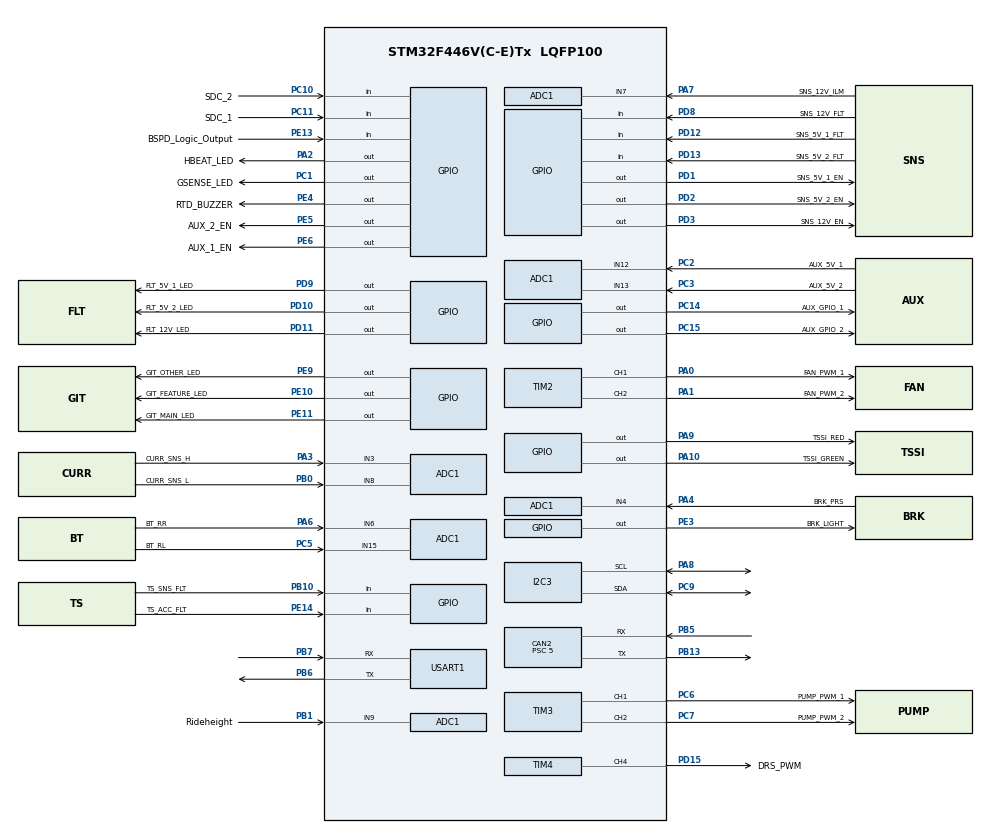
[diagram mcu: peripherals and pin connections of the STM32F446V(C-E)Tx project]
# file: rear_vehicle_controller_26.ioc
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ADC1.Channel-0\#ChannelRegularConversion=ADC_CHANNEL_3
ADC1.Channel-1\#ChannelRegularConversion=ADC_CHANNEL_4
ADC1.Channel-2\#ChannelRegularConversion=ADC_CHANNEL_6
ADC1.Channel-3\#ChannelRegularConversion=ADC_CHANNEL_7
ADC1.Channel-4\#ChannelRegularConversion=ADC_CHANNEL_8
ADC1.Channel-5\#ChannelRegularConversion=ADC_CHANNEL_9
ADC1.Channel-6\#ChannelRegularConversion=ADC_CHANNEL_12
ADC1.Channel-7\#ChannelRegularConversion=ADC_CHANNEL_13
ADC1.Channel-8\#ChannelRegularConversion=ADC_CHANNEL_15
ADC1.ClockPrescaler=ADC_CLOCK_SYNC_PCLK_DIV4
ADC1.ContinuousConvMode=ENABLE
ADC1.DMAContinuousRequests=ENABLE
ADC1.NbrOfConversion=9
ADC1.NbrOfConversionFlag=1
ADC1.Rank-0\#ChannelRegularConversion=1
ADC1.Rank-1\#ChannelRegularConversion=2
ADC1.Rank-2\#ChannelRegularConversion=3
ADC1.Rank-3\#ChannelRegularConversion=4
ADC1.Rank-4\#ChannelRegularConversion=5
ADC1.Rank-5\#ChannelRegularConversion=6
ADC1.Rank-6\#ChannelRegularConversion=7
ADC1.Rank-7\#ChannelRegularConversion=8
ADC1.Rank-8\#ChannelRegularConversion=9
ADC1.SamplingTime-0\#ChannelRegularConversion=ADC_SAMPLETIME_480CYCLES
ADC1.SamplingTime-1\#ChannelRegularConversion=ADC_SAMPLETIME_480CYCLES
ADC1.SamplingTime-2\#ChannelRegularConversion=ADC_SAMPLETIME_480CYCLES
ADC1.SamplingTime-3\#ChannelRegularConversion=ADC_SAMPLETIME_480CYCLES
ADC1.SamplingTime-4\#ChannelRegularConversion=ADC_SAMPLETIME_480CYCLES
ADC1.SamplingTime-5\#ChannelRegularConversion=ADC_SAMPLETIME_480CYCLES
ADC1.SamplingTime-6\#ChannelRegularConversion=ADC_SAMPLETIME_480CYCLES
ADC1.SamplingTime-7\#ChannelRegularConversion=ADC_SAMPLETIME_480CYCLES
ADC1.SamplingTime-8\#ChannelRegularConversion=ADC_SAMPLETIME_480CYCLES
ADC1.master=1
CAN2.ABOM=ENABLE
CAN2.AWUM=ENABLE
CAN2.BS1=CAN_BS1_6TQ
CAN2.CalculateBaudRate=1000000
CAN2.CalculateTimeBit=1000
CAN2.CalculateTimeQuantum=125.0
CAN2.Prescaler=5
Dma.ADC1.0.Direction=DMA_PERIPH_TO_MEMORY
Dma.ADC1.0.FIFOMode=DMA_FIFOMODE_DISABLE
Dma.ADC1.0.Instance=DMA2_Stream0
Dma.ADC1.0.MemDataAlignment=DMA_MDATAALIGN_HALFWORD
Dma.ADC1.0.MemInc=DMA_MINC_ENABLE
Dma.ADC1.0.Mode=DMA_CIRCULAR
Dma.ADC1.0.PeriphDataAlignment=DMA_PDATAALIGN_HALFWORD
Dma.ADC1.0.PeriphInc=DMA_PINC_DISABLE
Dma.ADC1.0.Priority=DMA_PRIORITY_LOW
Dma.Request0=ADC1
FREERTOS.Tasks01=main_task,0,1024,task_MainTask,Default,NULL,Dynamic,NULL,NULL;gcan_buffering,1,1024,gcanBufferHandling,Default,NULL,Dynamic,NULL,NULL
FREERTOS.configENABLE_FPU=1
Mcu.Family=STM32F4
Mcu.Name=STM32F446V(C-E)Tx
Mcu.Package=LQFP100
NVIC.CAN2_RX0_IRQn=true\:5\:0\:false\:false\:true\:true\:true\:true\:true
NVIC.CAN2_RX1_IRQn=true\:5\:0\:false\:false\:true\:true\:true\:true\:true
NVIC.CAN2_TX_IRQn=true\:5\:0\:false\:false\:true\:true\:true\:true\:true
NVIC.DMA2_Stream0_IRQn=true\:5\:0\:false\:false\:true\:true\:false\:true\:true
NVIC.PriorityGroup=NVIC_PRIORITYGROUP_4
NVIC.TIM1_UP_TIM10_IRQn=true\:5\:0\:false\:false\:true\:true\:true\:true\:true
NVIC.TIM6_DAC_IRQn=true\:15\:0\:false\:false\:true\:false\:false\:true\:true
NVIC.TimeBase=TIM6_DAC_IRQn
NVIC.TimeBaseIP=TIM6
PA0-WKUP.GPIO_Label=FAN_PWM_1
PA0-WKUP.Signal=S_TIM2_CH1_ETR
PA1.GPIO_Label=FAN_PWM_2
PA1.Signal=S_TIM2_CH2
PA10.GPIO_Label=TSSI_GREEN
PA10.Signal=GPIO_Output
PA13.Mode=Serial_Wire
PA13.Signal=SYS_JTMS-SWDIO
PA14.Mode=Serial_Wire
PA14.Signal=SYS_JTCK-SWCLK
PA2.GPIO_Label=HBEAT_LED
PA2.Signal=GPIO_Output
PA3.GPIO_Label=CURR_SNS_H
PA3.Signal=ADCx_IN3
PA4.GPIO_Label=BRK_PRS
PA4.Signal=ADCx_IN4
PA6.GPIO_Label=BT_RR
PA6.Signal=ADCx_IN6
PA7.GPIO_Label=SNS_12V_ILM
PA7.Signal=ADCx_IN7
PA8.Mode=I2C
PA8.Signal=I2C3_SCL
PA9.GPIO_Label=TSSI_RED
PA9.Signal=GPIO_Output
PB0.GPIO_Label=CURR_SNS_L
PB0.Signal=ADCx_IN8
PB1.GPIO_Label=Rideheight
PB1.Signal=ADCx_IN9
PB10.GPIO_Label=TS_SNS_FLT
PB10.Signal=GPIO_Input
PB13.Mode=CAN_Activate
PB13.Signal=CAN2_TX
PB3.Signal=SYS_JTDO-SWO
PB5.Mode=CAN_Activate
PB5.Signal=CAN2_RX
PB6.Mode=Asynchronous
PB6.Signal=USART1_TX
PB7.Mode=Asynchronous
PB7.Signal=USART1_RX
PC1.GPIO_Label=GSENSE_LED
PC1.Signal=GPIO_Output
PC10.GPIO_Label=SDC_2
PC10.Signal=GPIO_Input
PC11.GPIO_Label=SDC_1
PC11.Signal=GPIO_Input
PC14-OSC32_IN.GPIO_Label=AUX_GPIO_1
PC14-OSC32_IN.Signal=GPIO_Output
PC15-OSC32_OUT.GPIO_Label=AUX_GPIO_2
PC15-OSC32_OUT.Signal=GPIO_Output
PC2.GPIO_Label=AUX_5V_1
PC2.Signal=ADCx_IN12
PC3.GPIO_Label=AUX_5V_2
PC3.Signal=ADCx_IN13
PC5.GPIO_Label=BT_RL
PC5.Signal=ADCx_IN15
PC6.GPIO_Label=PUMP_PWM_1
PC6.Signal=S_TIM3_CH1
PC7.GPIO_Label=PUMP_PWM_2
PC7.Signal=S_TIM3_CH2
PC9.Mode=I2C
PC9.Signal=I2C3_SDA
PD1.GPIO_Label=SNS_5V_1_EN
PD1.Signal=GPIO_Output
PD10.GPIO_Label=FLT_5V_2_LED
PD10.Signal=GPIO_Output
PD11.GPIO_Label=FLT_12V_LED
PD11.Signal=GPIO_Output
PD12.GPIO_Label=SNS_5V_1_FLT
PD12.Signal=GPIO_Input
PD13.GPIO_Label=SNS_5V_2_FLT
PD13.Signal=GPIO_Input
PD15.GPIO_Label=DRS_PWM
PD15.Signal=S_TIM4_CH4
PD2.GPIO_Label=SNS_5V_2_EN
PD2.Signal=GPIO_Output
PD3.GPIO_Label=SNS_12V_EN
PD3.Signal=GPIO_Output
PD8.GPIO_Label=SNS_12V_FLT
PD8.Signal=GPIO_Input
PD9.GPIO_Label=FLT_5V_1_LED
PD9.Signal=GPIO_Output
PE10.GPIO_Label=GIT_FEATURE_LED
PE10.Signal=GPIO_Output
PE11.GPIO_Label=GIT_MAIN_LED
PE11.Signal=GPIO_Output
PE13.GPIO_Label=BSPD_Logic_Output
PE13.Signal=GPIO_Input
PE14.GPIO_Label=TS_ACC_FLT
PE14.Signal=GPIO_Input
PE3.GPIO_Label=BRK_LIGHT
PE3.Signal=GPIO_Output
PE4.GPIO_Label=RTD_BUZZER
PE4.Signal=GPIO_Output
PE5.GPIO_Label=AUX_2_EN
PE5.Signal=GPIO_Output
PE6.GPIO_Label=AUX_1_EN
PE6.Signal=GPIO_Output
PE9.GPIO_Label=GIT_OTHER_LED
PE9.Signal=GPIO_Output
PH0-OSC_IN.Mode=HSE-External-Clock-Source
PH0-OSC_IN.Signal=RCC_OSC_IN
PH1-OSC_OUT.Mode=HSE-External-Clock-Source
PH1-OSC_OUT.Signal=RCC_OSC_OUT
ProjectManager.HeapSize=0x200
ProjectManager.StackSize=0x400
ProjectManager.TargetToolchain=CMake
RCC.AHBFreq_Value=160000000
RCC.APB1CLKDivider=RCC_HCLK_DIV4
RCC.APB1Freq_Value=40000000
RCC.APB1TimFreq_Value=80000000
RCC.APB2CLKDivider=RCC_HCLK_DIV16
RCC.APB2Freq_Value=10000000
RCC.APB2TimFreq_Value=20000000
RCC.CortexFreq_Value=160000000
RCC.HCLKFreq_Value=160000000
RCC.HSE_VALUE=24000000
RCC.PLLM=12
RCC.PLLN=160
RCC.PLLSourceVirtual=RCC_PLLSOURCE_HSE
RCC.SYSCLKFreq_VALUE=160000000
RCC.SYSCLKSource=RCC_SYSCLKSOURCE_PLLCLK
RCC.USBFreq_Value=160000000
RCC.VCOOutputFreq_Value=320000000
SH.ADCx_IN12.0=ADC1_IN12,IN12
SH.ADCx_IN13.0=ADC1_IN13,IN13
SH.ADCx_IN15.0=ADC1_IN15,IN15
SH.ADCx_IN3.0=ADC1_IN3,IN3
SH.ADCx_IN4.0=ADC1_IN4,IN4
SH.ADCx_IN6.0=ADC1_IN6,IN6
SH.ADCx_IN7.0=ADC1_IN7,IN7
SH.ADCx_IN8.0=ADC1_IN8,IN8
SH.ADCx_IN9.0=ADC1_IN9,IN9
SH.S_TIM2_CH1_ETR.0=TIM2_CH1,PWM Generation1 CH1
SH.S_TIM2_CH2.0=TIM2_CH2,PWM Generation2 CH2
SH.S_TIM3_CH1.0=TIM3_CH1,PWM Generation1 CH1
SH.S_TIM3_CH2.0=TIM3_CH2,PWM Generation2 CH2
SH.S_TIM4_CH4.0=TIM4_CH4,PWM Generation4 CH4
TIM2.Channel-PWM\ Generation1\ CH1=TIM_CHANNEL_1
TIM2.Channel-PWM\ Generation2\ CH2=TIM_CHANNEL_2
TIM3.Channel-PWM\ Generation1\ CH1=TIM_CHANNEL_1
TIM3.Channel-PWM\ Generation2\ CH2=TIM_CHANNEL_2
TIM4.Channel-PWM\ Generation4\ CH4=TIM_CHANNEL_4
TIM4.Period=30100
TIM4.Prescaler=8-1
TIM4.Pulse-PWM\ Generation4\ CH4=30000
USART1.VirtualMode=VM_ASYNC
VP_FREERTOS_VS_CMSIS_V1.Mode=CMSIS_V1
VP_SYS_VS_tim6.Mode=TIM6
VP_TIM10_VS_ClockSourceINT.Mode=Enable_Timer
VP_TIM2_VS_ClockSourceINT.Mode=Internal
VP_TIM3_VS_ClockSourceINT.Mode=Internal
VP_TIM4_VS_ClockSourceINT.Mode=Internal
board=custom

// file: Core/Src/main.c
/* USER CODE BEGIN Header */
/**
  ******************************************************************************
  * @file           : main.c
  * @brief          : Main program body
  ******************************************************************************
  * @attention
  *
  * Copyright (c) 2025 STMicroelectronics.
  * All rights reserved.
  *
  * This software is licensed under terms that can be found in the LICENSE file
  * in the root directory of this software component.
  * If no LICENSE file comes with this software, it is provided AS-IS.
  *
  ******************************************************************************
  */
/* USER CODE END Header */
#include "main.h"
#include "cmsis_os.h"
#include "adc.h"
#include "can.h"
#include "dma.h"
#include "i2c.h"
#include "tim.h"
#include "usart.h"
#include "gpio.h"

/* USER CODE BEGIN Includes */
#include "rvc.h"
#include "GopherCAN.h"
#include "gopher_sense.h"
/* USER CODE END Includes */

void SystemClock_Config(void);
void MX_FREERTOS_Init(void);

int main(void)
{

  /* MCU Configuration--------------------------------------------------------*/

  /* Reset of all peripherals, Initializes the Flash interface and the Systick. */
  HAL_Init();

  /* Configure the system clock */
  SystemClock_Config();

  /* Initialize all configured peripherals */
  MX_GPIO_Init();
  MX_DMA_Init();
  MX_ADC1_Init();
  MX_CAN2_Init();
  MX_TIM10_Init();
  MX_I2C3_Init();
  MX_TIM2_Init();
  MX_TIM3_Init();
  MX_TIM4_Init();
  MX_USART1_UART_Init();
  /* USER CODE BEGIN 2 */
  init_rvc(&hcan2);
  gsense_init(&hcan2, &hadc1, NULL, NULL, &htim10, GSENSE_LED_GPIO_Port, GSENSE_LED_Pin);
  /* USER CODE END 2 */

  /* Call init function for freertos objects (in cmsis_os2.c) */
  MX_FREERTOS_Init();

  /* Start scheduler */
  osKernelStart();

  /* We should never get here as control is now taken by the scheduler */

  /* Infinite loop */
  while (1)
  {

  }
}

void SystemClock_Config(void)
{
  RCC_OscInitTypeDef RCC_OscInitStruct = {0};
  RCC_ClkInitTypeDef RCC_ClkInitStruct = {0};

  /** Configure the main internal regulator output voltage
  */
  __HAL_RCC_PWR_CLK_ENABLE();
  __HAL_PWR_VOLTAGESCALING_CONFIG(PWR_REGULATOR_VOLTAGE_SCALE1);

  /** Initializes the RCC Oscillators according to the specified parameters
  * in the RCC_OscInitTypeDef structure.
  */
  RCC_OscInitStruct.OscillatorType = RCC_OSCILLATORTYPE_HSE;
  RCC_OscInitStruct.HSEState = RCC_HSE_BYPASS;
  RCC_OscInitStruct.PLL.PLLState = RCC_PLL_ON;
  RCC_OscInitStruct.PLL.PLLSource = RCC_PLLSOURCE_HSE;
  RCC_OscInitStruct.PLL.PLLM = 12;
  RCC_OscInitStruct.PLL.PLLN = 160;
  RCC_OscInitStruct.PLL.PLLP = RCC_PLLP_DIV2;
  RCC_OscInitStruct.PLL.PLLQ = 2;
  RCC_OscInitStruct.PLL.PLLR = 2;
  if (HAL_RCC_OscConfig(&RCC_OscInitStruct) != HAL_OK)
  {
    Error_Handler();
  }

  /** Initializes the CPU, AHB and APB buses clocks
  */
  RCC_ClkInitStruct.ClockType = RCC_CLOCKTYPE_HCLK|RCC_CLOCKTYPE_SYSCLK
                              |RCC_CLOCKTYPE_PCLK1|RCC_CLOCKTYPE_PCLK2;
  RCC_ClkInitStruct.SYSCLKSource = RCC_SYSCLKSOURCE_PLLCLK;
  RCC_ClkInitStruct.AHBCLKDivider = RCC_SYSCLK_DIV1;
  RCC_ClkInitStruct.APB1CLKDivider = RCC_HCLK_DIV4;
  RCC_ClkInitStruct.APB2CLKDivider = RCC_HCLK_DIV2;

  if (HAL_RCC_ClockConfig(&RCC_ClkInitStruct, FLASH_LATENCY_5) != HAL_OK)
  {
    Error_Handler();
  }
}

static void MX_ADC1_Init(void)
{

  ADC_ChannelConfTypeDef sConfig = {0};

  /** Configure the global features of the ADC (Clock, Resolution, Data Alignment and number of conversion)
  */
  hadc1.Instance = ADC1;
  hadc1.Init.ClockPrescaler = ADC_CLOCK_SYNC_PCLK_DIV4;
  hadc1.Init.Resolution = ADC_RESOLUTION_12B;
  hadc1.Init.ScanConvMode = ENABLE;
  hadc1.Init.ContinuousConvMode = ENABLE;
  hadc1.Init.DiscontinuousConvMode = DISABLE;
  hadc1.Init.ExternalTrigConvEdge = ADC_EXTERNALTRIGCONVEDGE_NONE;
  hadc1.Init.ExternalTrigConv = ADC_SOFTWARE_START;
  hadc1.Init.DataAlign = ADC_DATAALIGN_RIGHT;
  hadc1.Init.NbrOfConversion = 9;
  hadc1.Init.DMAContinuousRequests = ENABLE;
  hadc1.Init.EOCSelection = ADC_EOC_SINGLE_CONV;
  if (HAL_ADC_Init(&hadc1) != HAL_OK)
  {
    Error_Handler();
  }

  /** Configure for the selected ADC regular channel its corresponding rank in the sequencer and its sample time.
  */
  sConfig.Channel = ADC_CHANNEL_3;
  sConfig.Rank = 1;
  sConfig.SamplingTime = ADC_SAMPLETIME_480CYCLES;
  if (HAL_ADC_ConfigChannel(&hadc1, &sConfig) != HAL_OK)
  {
    Error_Handler();
  }

  /** Configure for the selected ADC regular channel its corresponding rank in the sequencer and its sample time.
  */
  sConfig.Channel = ADC_CHANNEL_4;
  sConfig.Rank = 2;
  if (HAL_ADC_ConfigChannel(&hadc1, &sConfig) != HAL_OK)
  {
    Error_Handler();
  }

  /** Configure for the selected ADC regular channel its corresponding rank in the sequencer and its sample time.
  */
  sConfig.Channel = ADC_CHANNEL_6;
  sConfig.Rank = 3;
  if (HAL_ADC_ConfigChannel(&hadc1, &sConfig) != HAL_OK)
  {
    Error_Handler();
  }

  /** Configure for the selected ADC regular channel its corresponding rank in the sequencer and its sample time.
  */
  sConfig.Channel = ADC_CHANNEL_7;
  sConfig.Rank = 4;
  if (HAL_ADC_ConfigChannel(&hadc1, &sConfig) != HAL_OK)
  {
    Error_Handler();
  }

  /** Configure for the selected ADC regular channel its corresponding rank in the sequencer and its sample time.
  */
  sConfig.Channel = ADC_CHANNEL_8;
  sConfig.Rank = 5;
  if (HAL_ADC_ConfigChannel(&hadc1, &sConfig) != HAL_OK)
  {
    Error_Handler();
  }

  /** Configure for the selected ADC regular channel its corresponding rank in the sequencer and its sample time.
  */
  sConfig.Channel = ADC_CHANNEL_9;
  sConfig.Rank = 6;
  if (HAL_ADC_ConfigChannel(&hadc1, &sConfig) != HAL_OK)
  {
    Error_Handler();
  }

  /** Configure for the selected ADC regular channel its corresponding rank in the sequencer and its sample time.
  */
  sConfig.Channel = ADC_CHANNEL_12;
  sConfig.Rank = 7;
  if (HAL_ADC_ConfigChannel(&hadc1, &sConfig) != HAL_OK)
  {
    Error_Handler();
  }

  /** Configure for the selected ADC regular channel its corresponding rank in the sequencer and its sample time.
  */
  sConfig.Channel = ADC_CHANNEL_13;
  sConfig.Rank = 8;
  if (HAL_ADC_ConfigChannel(&hadc1, &sConfig) != HAL_OK)
  {
    Error_Handler();
  }

  /** Configure for the selected ADC regular channel its corresponding rank in the sequencer and its sample time.
  */
  sConfig.Channel = ADC_CHANNEL_15;
  sConfig.Rank = 9;
  if (HAL_ADC_ConfigChannel(&hadc1, &sConfig) != HAL_OK)
  {
    Error_Handler();
  }

}

static void MX_CAN2_Init(void)
{

  hcan2.Instance = CAN2;
  hcan2.Init.Prescaler = 5;
  hcan2.Init.Mode = CAN_MODE_NORMAL;
  hcan2.Init.SyncJumpWidth = CAN_SJW_1TQ;
  hcan2.Init.TimeSeg1 = CAN_BS1_6TQ;
  hcan2.Init.TimeSeg2 = CAN_BS2_1TQ;
  hcan2.Init.TimeTriggeredMode = DISABLE;
  hcan2.Init.AutoBusOff = ENABLE;
  hcan2.Init.AutoWakeUp = ENABLE;
  hcan2.Init.AutoRetransmission = DISABLE;
  hcan2.Init.ReceiveFifoLocked = DISABLE;
  hcan2.Init.TransmitFifoPriority = DISABLE;
  if (HAL_CAN_Init(&hcan2) != HAL_OK)
  {
    Error_Handler();
  }

}

static void MX_I2C3_Init(void)
{

  hi2c3.Instance = I2C3;
  hi2c3.Init.ClockSpeed = 100000;
  hi2c3.Init.DutyCycle = I2C_DUTYCYCLE_2;
  hi2c3.Init.OwnAddress1 = 0;
  hi2c3.Init.AddressingMode = I2C_ADDRESSINGMODE_7BIT;
  hi2c3.Init.DualAddressMode = I2C_DUALADDRESS_DISABLE;
  hi2c3.Init.OwnAddress2 = 0;
  hi2c3.Init.GeneralCallMode = I2C_GENERALCALL_DISABLE;
  hi2c3.Init.NoStretchMode = I2C_NOSTRETCH_DISABLE;
  if (HAL_I2C_Init(&hi2c3) != HAL_OK)
  {
    Error_Handler();
  }

}

static void MX_TIM2_Init(void)
{

  TIM_MasterConfigTypeDef sMasterConfig = {0};
  TIM_OC_InitTypeDef sConfigOC = {0};

  htim2.Instance = TIM2;
  htim2.Init.Prescaler = 0;
  htim2.Init.CounterMode = TIM_COUNTERMODE_UP;
  htim2.Init.Period = 4294967295;
  htim2.Init.ClockDivision = TIM_CLOCKDIVISION_DIV1;
  htim2.Init.AutoReloadPreload = TIM_AUTORELOAD_PRELOAD_DISABLE;
  if (HAL_TIM_PWM_Init(&htim2) != HAL_OK)
  {
    Error_Handler();
  }
  sMasterConfig.MasterOutputTrigger = TIM_TRGO_RESET;
  sMasterConfig.MasterSlaveMode = TIM_MASTERSLAVEMODE_DISABLE;
  if (HAL_TIMEx_MasterConfigSynchronization(&htim2, &sMasterConfig) != HAL_OK)
  {
    Error_Handler();
  }
  sConfigOC.OCMode = TIM_OCMODE_PWM1;
  sConfigOC.Pulse = 0;
  sConfigOC.OCPolarity = TIM_OCPOLARITY_HIGH;
  sConfigOC.OCFastMode = TIM_OCFAST_DISABLE;
  if (HAL_TIM_PWM_ConfigChannel(&htim2, &sConfigOC, TIM_CHANNEL_1) != HAL_OK)
  {
    Error_Handler();
  }
  if (HAL_TIM_PWM_ConfigChannel(&htim2, &sConfigOC, TIM_CHANNEL_2) != HAL_OK)
  {
    Error_Handler();
  }
  HAL_TIM_MspPostInit(&htim2);

}

static void MX_TIM3_Init(void)
{

  TIM_MasterConfigTypeDef sMasterConfig = {0};
  TIM_OC_InitTypeDef sConfigOC = {0};

  htim3.Instance = TIM3;
  htim3.Init.Prescaler = 0;
  htim3.Init.CounterMode = TIM_COUNTERMODE_UP;
  htim3.Init.Period = 65535;
  htim3.Init.ClockDivision = TIM_CLOCKDIVISION_DIV1;
  htim3.Init.AutoReloadPreload = TIM_AUTORELOAD_PRELOAD_DISABLE;
  if (HAL_TIM_PWM_Init(&htim3) != HAL_OK)
  {
    Error_Handler();
  }
  sMasterConfig.MasterOutputTrigger = TIM_TRGO_RESET;
  sMasterConfig.MasterSlaveMode = TIM_MASTERSLAVEMODE_DISABLE;
  if (HAL_TIMEx_MasterConfigSynchronization(&htim3, &sMasterConfig) != HAL_OK)
  {
    Error_Handler();
  }
  sConfigOC.OCMode = TIM_OCMODE_PWM1;
  sConfigOC.Pulse = 0;
  sConfigOC.OCPolarity = TIM_OCPOLARITY_HIGH;
  sConfigOC.OCFastMode = TIM_OCFAST_DISABLE;
  if (HAL_TIM_PWM_ConfigChannel(&htim3, &sConfigOC, TIM_CHANNEL_1) != HAL_OK)
  {
    Error_Handler();
  }
  if (HAL_TIM_PWM_ConfigChannel(&htim3, &sConfigOC, TIM_CHANNEL_2) != HAL_OK)
  {
    Error_Handler();
  }
  HAL_TIM_MspPostInit(&htim3);

}

static void MX_TIM4_Init(void)
{

  TIM_MasterConfigTypeDef sMasterConfig = {0};
  TIM_OC_InitTypeDef sConfigOC = {0};

  htim4.Instance = TIM4;
  htim4.Init.Prescaler = 0;
  htim4.Init.CounterMode = TIM_COUNTERMODE_UP;
  htim4.Init.Period = 65535;
  htim4.Init.ClockDivision = TIM_CLOCKDIVISION_DIV1;
  htim4.Init.AutoReloadPreload = TIM_AUTORELOAD_PRELOAD_DISABLE;
  if (HAL_TIM_PWM_Init(&htim4) != HAL_OK)
  {
    Error_Handler();
  }
  sMasterConfig.MasterOutputTrigger = TIM_TRGO_RESET;
  sMasterConfig.MasterSlaveMode = TIM_MASTERSLAVEMODE_DISABLE;
  if (HAL_TIMEx_MasterConfigSynchronization(&htim4, &sMasterConfig) != HAL_OK)
  {
    Error_Handler();
  }
  sConfigOC.OCMode = TIM_OCMODE_PWM1;
  sConfigOC.Pulse = 0;
  sConfigOC.OCPolarity = TIM_OCPOLARITY_HIGH;
  sConfigOC.OCFastMode = TIM_OCFAST_DISABLE;
  if (HAL_TIM_PWM_ConfigChannel(&htim4, &sConfigOC, TIM_CHANNEL_4) != HAL_OK)
  {
    Error_Handler();
  }
  HAL_TIM_MspPostInit(&htim4);

}

static void MX_TIM10_Init(void)
{

  htim10.Instance = TIM10;
  htim10.Init.Prescaler = 0;
  htim10.Init.CounterMode = TIM_COUNTERMODE_UP;
  htim10.Init.Period = 65535;
  htim10.Init.ClockDivision = TIM_CLOCKDIVISION_DIV1;
  htim10.Init.AutoReloadPreload = TIM_AUTORELOAD_PRELOAD_DISABLE;
  if (HAL_TIM_Base_Init(&htim10) != HAL_OK)
  {
    Error_Handler();
  }

}

static void MX_USART1_UART_Init(void)
{

  huart1.Instance = USART1;
  huart1.Init.BaudRate = 115200;
  huart1.Init.WordLength = UART_WORDLENGTH_8B;
  huart1.Init.StopBits = UART_STOPBITS_1;
  huart1.Init.Parity = UART_PARITY_NONE;
  huart1.Init.Mode = UART_MODE_TX_RX;
  huart1.Init.HwFlowCtl = UART_HWCONTROL_NONE;
  huart1.Init.OverSampling = UART_OVERSAMPLING_16;
  if (HAL_UART_Init(&huart1) != HAL_OK)
  {
    Error_Handler();
  }

}

static void MX_DMA_Init(void)
{

  /* DMA controller clock enable */
  __HAL_RCC_DMA2_CLK_ENABLE();

  /* DMA interrupt init */
  /* DMA2_Stream0_IRQn interrupt configuration */
  HAL_NVIC_SetPriority(DMA2_Stream0_IRQn, 5, 0);
  HAL_NVIC_EnableIRQ(DMA2_Stream0_IRQn);

}

static void MX_GPIO_Init(void)
{
  GPIO_InitTypeDef GPIO_InitStruct = {0};

  /* GPIO Ports Clock Enable */
  __HAL_RCC_GPIOE_CLK_ENABLE();
  __HAL_RCC_GPIOC_CLK_ENABLE();
  __HAL_RCC_GPIOH_CLK_ENABLE();
  __HAL_RCC_GPIOA_CLK_ENABLE();
  __HAL_RCC_GPIOB_CLK_ENABLE();
  __HAL_RCC_GPIOD_CLK_ENABLE();

  /*Configure GPIO pin Output Level */
  HAL_GPIO_WritePin(GPIOE, BRK_LIGHT_Pin|RTD_BUZZER_Pin|AUX_2_EN_Pin|AUX_1_EN_Pin
                          |GIT_OTHER_LED_Pin|GIT_FEATURE_LED_Pin|GIT_MAIN_LED_Pin, GPIO_PIN_RESET);

  /*Configure GPIO pin Output Level */
  HAL_GPIO_WritePin(GPIOC, AUX_GPIO_1_Pin|AUX_GPIO_2_Pin|GSENSE_LED_Pin, GPIO_PIN_RESET);

  /*Configure GPIO pin Output Level */
  HAL_GPIO_WritePin(GPIOA, HBEAT_LED_Pin|TSSI_RED_Pin|TSSI_GREEN_Pin, GPIO_PIN_RESET);

  /*Configure GPIO pin Output Level */
  HAL_GPIO_WritePin(GPIOD, SNS_FLT_5V_1_LED_Pin|SNS_FLT_5V_2_LED_Pin|SNS_FLT_12V_LED_Pin|SNS_5V_1_EN_Pin
                          |SNS_5V_2_EN_Pin|SNS_12V_EN_Pin, GPIO_PIN_RESET);

  /*Configure GPIO pins : BRK_LIGHT_Pin RTD_BUZZER_Pin AUX_2_EN_Pin AUX_1_EN_Pin
                           GIT_OTHER_LED_Pin GIT_FEATURE_LED_Pin GIT_MAIN_LED_Pin */
  GPIO_InitStruct.Pin = BRK_LIGHT_Pin|RTD_BUZZER_Pin|AUX_2_EN_Pin|AUX_1_EN_Pin
                          |GIT_OTHER_LED_Pin|GIT_FEATURE_LED_Pin|GIT_MAIN_LED_Pin;
  GPIO_InitStruct.Mode = GPIO_MODE_OUTPUT_PP;
  GPIO_InitStruct.Pull = GPIO_NOPULL;
  GPIO_InitStruct.Speed = GPIO_SPEED_FREQ_LOW;
  HAL_GPIO_Init(GPIOE, &GPIO_InitStruct);

  /*Configure GPIO pins : AUX_GPIO_1_Pin AUX_GPIO_2_Pin GSENSE_LED_Pin */
  GPIO_InitStruct.Pin = AUX_GPIO_1_Pin|AUX_GPIO_2_Pin|GSENSE_LED_Pin;
  GPIO_InitStruct.Mode = GPIO_MODE_OUTPUT_PP;
  GPIO_InitStruct.Pull = GPIO_NOPULL;
  GPIO_InitStruct.Speed = GPIO_SPEED_FREQ_LOW;
  HAL_GPIO_Init(GPIOC, &GPIO_InitStruct);

  /*Configure GPIO pins : HBEAT_LED_Pin TSSI_RED_Pin TSSI_GREEN_Pin */
  GPIO_InitStruct.Pin = HBEAT_LED_Pin|TSSI_RED_Pin|TSSI_GREEN_Pin;
  GPIO_InitStruct.Mode = GPIO_MODE_OUTPUT_PP;
  GPIO_InitStruct.Pull = GPIO_NOPULL;
  GPIO_InitStruct.Speed = GPIO_SPEED_FREQ_LOW;
  HAL_GPIO_Init(GPIOA, &GPIO_InitStruct);

  /*Configure GPIO pins : BSPD_Logic_Output_Pin TS_ACC_FLT_Pin */
  GPIO_InitStruct.Pin = BSPD_Logic_Output_Pin|TS_ACC_FLT_Pin;
  GPIO_InitStruct.Mode = GPIO_MODE_INPUT;
  GPIO_InitStruct.Pull = GPIO_NOPULL;
  HAL_GPIO_Init(GPIOE, &GPIO_InitStruct);

  /*Configure GPIO pin : TS_SNS_FLT_Pin */
  GPIO_InitStruct.Pin = TS_SNS_FLT_Pin;
  GPIO_InitStruct.Mode = GPIO_MODE_INPUT;
  GPIO_InitStruct.Pull = GPIO_NOPULL;
  HAL_GPIO_Init(TS_SNS_FLT_GPIO_Port, &GPIO_InitStruct);

  /*Configure GPIO pins : SNS_12V_FLT_Pin SNS_5V_1_FLT_Pin SNS_5V_2_FLT_Pin */
  GPIO_InitStruct.Pin = SNS_12V_FLT_Pin|SNS_5V_1_FLT_Pin|SNS_5V_2_FLT_Pin;
  GPIO_InitStruct.Mode = GPIO_MODE_INPUT;
  GPIO_InitStruct.Pull = GPIO_NOPULL;
  HAL_GPIO_Init(GPIOD, &GPIO_InitStruct);

  /*Configure GPIO pins : SNS_FLT_5V_1_LED_Pin SNS_FLT_5V_2_LED_Pin SNS_FLT_12V_LED_Pin SNS_5V_1_EN_Pin
                           SNS_5V_2_EN_Pin SNS_12V_EN_Pin */
  GPIO_InitStruct.Pin = SNS_FLT_5V_1_LED_Pin|SNS_FLT_5V_2_LED_Pin|SNS_FLT_12V_LED_Pin|SNS_5V_1_EN_Pin
                          |SNS_5V_2_EN_Pin|SNS_12V_EN_Pin;
  GPIO_InitStruct.Mode = GPIO_MODE_OUTPUT_PP;
  GPIO_InitStruct.Pull = GPIO_NOPULL;
  GPIO_InitStruct.Speed = GPIO_SPEED_FREQ_LOW;
  HAL_GPIO_Init(GPIOD, &GPIO_InitStruct);

  /*Configure GPIO pins : SDC_2_Pin SDC_1_Pin */
  GPIO_InitStruct.Pin = SDC_2_Pin|SDC_1_Pin;
  GPIO_InitStruct.Mode = GPIO_MODE_INPUT;
  GPIO_InitStruct.Pull = GPIO_NOPULL;
  HAL_GPIO_Init(GPIOC, &GPIO_InitStruct);

}

void HAL_TIM_PeriodElapsedCallback(TIM_HandleTypeDef *htim)
{
  if (htim->Instance == TIM6) {
    HAL_IncTick();
  }
  /* USER CODE BEGIN Callback 1 */
  else if(htim->Instance == TIM10) {
  	  DAQ_TimerCallback(&htim10);
  }
  /* USER CODE END Callback 1 */
}

void Error_Handler(void)
{
  __disable_irq();
  while (1)
  {
  }
}

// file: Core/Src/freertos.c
/* USER CODE BEGIN Header */
/**
  ******************************************************************************
  * File Name          : freertos.c
  * Description        : Code for freertos applications
  ******************************************************************************
  * @attention
  *
  * Copyright (c) 2025 STMicroelectronics.
  * All rights reserved.
  *
  * This software is licensed under terms that can be found in the LICENSE file
  * in the root directory of this software component.
  * If no LICENSE file comes with this software, it is provided AS-IS.
  *
  ******************************************************************************
  */
/* USER CODE END Header */

#include "FreeRTOS.h"
#include "task.h"
#include "main.h"
#include "rvc.h"
#include "cmsis_os.h"

/* USER CODE BEGIN Includes */
#include "rvc.h"
/* USER CODE END Includes */

osThreadId main_taskHandle;
osThreadId gcan_bufferingHandle;

void task_MainTask(void const * argument);
void gcanBufferHandling(void const * argument);

void MX_FREERTOS_Init(void); /* (MISRA C 2004 rule 8.1) */

/* GetIdleTaskMemory prototype (linked to static allocation support) */
void vApplicationGetIdleTaskMemory( StaticTask_t **ppxIdleTaskTCBBuffer, StackType_t **ppxIdleTaskStackBuffer, uint32_t *pulIdleTaskStackSize );

/* USER CODE BEGIN GET_IDLE_TASK_MEMORY */
static StaticTask_t xIdleTaskTCBBuffer;
static StackType_t xIdleStack[configMINIMAL_STACK_SIZE];

void vApplicationGetIdleTaskMemory( StaticTask_t **ppxIdleTaskTCBBuffer, StackType_t **ppxIdleTaskStackBuffer, uint32_t *pulIdleTaskStackSize )
{
  *ppxIdleTaskTCBBuffer = &xIdleTaskTCBBuffer;
  *ppxIdleTaskStackBuffer = &xIdleStack[0];
  *pulIdleTaskStackSize = configMINIMAL_STACK_SIZE;
  /* place for user code */
}
/* USER CODE END GET_IDLE_TASK_MEMORY */

void MX_FREERTOS_Init(void) {

  /* Create the thread(s) */
  /* definition and creation of main_task */
  osThreadDef(main_task, task_MainTask, osPriorityNormal, 0, 1024);
  main_taskHandle = osThreadCreate(osThread(main_task), NULL);

  /* definition and creation of gcan_buffering */
  osThreadDef(gcan_buffering, gcanBufferHandling, osPriorityAboveNormal, 0, 1024);
  gcan_bufferingHandle = osThreadCreate(osThread(gcan_buffering), NULL);

}

void task_MainTask(void const * argument)
{
  /* USER CODE BEGIN task_MainTask */
  /* Infinite loop */
  for(;;)
  {
    main_loop();
    osDelay(1);
  }
  /* USER CODE END task_MainTask */
}

void gcanBufferHandling(void const * argument)
{
  /* USER CODE BEGIN gcanBufferHandling */
  /* Infinite loop */
  for(;;)
  {
    can_buffer_handling_loop();
    osDelay(1);
  }
  /* USER CODE END gcanBufferHandling */
}
